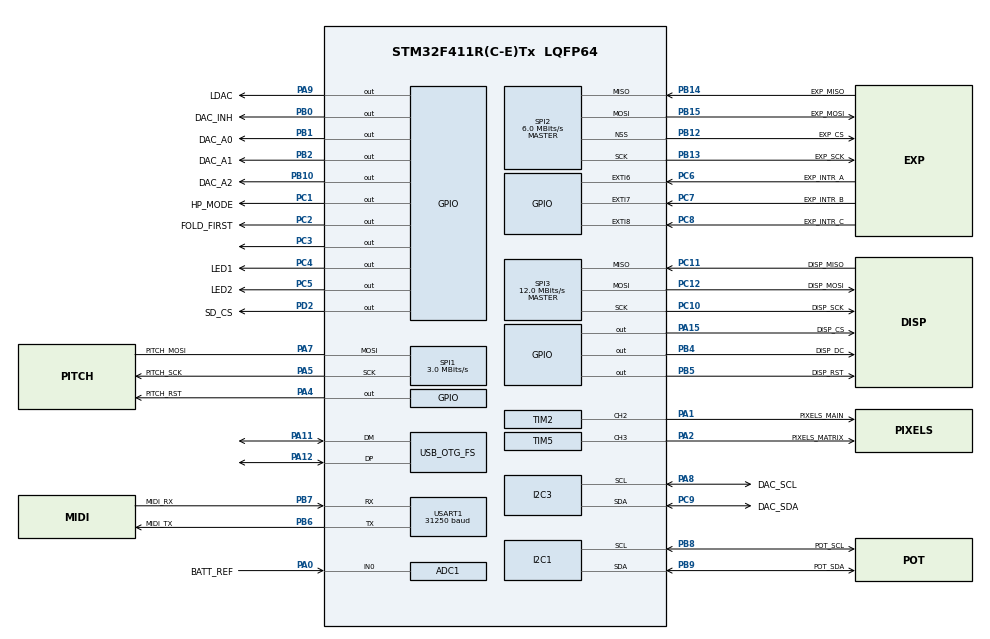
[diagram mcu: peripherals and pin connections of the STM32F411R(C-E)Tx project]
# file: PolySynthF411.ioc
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ADC1.Channel-2\#ChannelRegularConversion=ADC_CHANNEL_0
ADC1.NbrOfConversionFlag=1
ADC1.Rank-2\#ChannelRegularConversion=1
ADC1.SamplingTime-2\#ChannelRegularConversion=ADC_SAMPLETIME_3CYCLES
ADC1.master=1
Dma.I2C3_TX.2.Direction=DMA_MEMORY_TO_PERIPH
Dma.I2C3_TX.2.FIFOMode=DMA_FIFOMODE_DISABLE
Dma.I2C3_TX.2.Instance=DMA1_Stream4
Dma.I2C3_TX.2.MemDataAlignment=DMA_MDATAALIGN_BYTE
Dma.I2C3_TX.2.MemInc=DMA_MINC_ENABLE
Dma.I2C3_TX.2.Mode=DMA_NORMAL
Dma.I2C3_TX.2.PeriphDataAlignment=DMA_PDATAALIGN_BYTE
Dma.I2C3_TX.2.PeriphInc=DMA_PINC_DISABLE
Dma.I2C3_TX.2.Priority=DMA_PRIORITY_LOW
Dma.Request0=TIM5_CH3/UP
Dma.Request1=TIM2_CH2/CH4
Dma.Request2=I2C3_TX
Dma.Request3=SPI3_TX
Dma.Request4=SPI1_TX
Dma.SPI1_TX.4.Direction=DMA_MEMORY_TO_PERIPH
Dma.SPI1_TX.4.FIFOMode=DMA_FIFOMODE_DISABLE
Dma.SPI1_TX.4.Instance=DMA2_Stream2
Dma.SPI1_TX.4.MemDataAlignment=DMA_MDATAALIGN_HALFWORD
Dma.SPI1_TX.4.MemInc=DMA_MINC_ENABLE
Dma.SPI1_TX.4.Mode=DMA_CIRCULAR
Dma.SPI1_TX.4.PeriphDataAlignment=DMA_PDATAALIGN_HALFWORD
Dma.SPI1_TX.4.PeriphInc=DMA_PINC_DISABLE
Dma.SPI1_TX.4.Priority=DMA_PRIORITY_LOW
Dma.SPI3_TX.3.Direction=DMA_MEMORY_TO_PERIPH
Dma.SPI3_TX.3.FIFOMode=DMA_FIFOMODE_DISABLE
Dma.SPI3_TX.3.Instance=DMA1_Stream5
Dma.SPI3_TX.3.MemDataAlignment=DMA_MDATAALIGN_BYTE
Dma.SPI3_TX.3.MemInc=DMA_MINC_ENABLE
Dma.SPI3_TX.3.Mode=DMA_NORMAL
Dma.SPI3_TX.3.PeriphDataAlignment=DMA_PDATAALIGN_BYTE
Dma.SPI3_TX.3.PeriphInc=DMA_PINC_DISABLE
Dma.SPI3_TX.3.Priority=DMA_PRIORITY_LOW
Dma.TIM2_CH2/CH4.1.Direction=DMA_MEMORY_TO_PERIPH
Dma.TIM2_CH2/CH4.1.FIFOMode=DMA_FIFOMODE_DISABLE
Dma.TIM2_CH2/CH4.1.Instance=DMA1_Stream6
Dma.TIM2_CH2/CH4.1.MemDataAlignment=DMA_MDATAALIGN_HALFWORD
Dma.TIM2_CH2/CH4.1.MemInc=DMA_MINC_ENABLE
Dma.TIM2_CH2/CH4.1.Mode=DMA_CIRCULAR
Dma.TIM2_CH2/CH4.1.PeriphDataAlignment=DMA_PDATAALIGN_HALFWORD
Dma.TIM2_CH2/CH4.1.PeriphInc=DMA_PINC_DISABLE
Dma.TIM2_CH2/CH4.1.Priority=DMA_PRIORITY_LOW
Dma.TIM5_CH3/UP.0.Direction=DMA_MEMORY_TO_PERIPH
Dma.TIM5_CH3/UP.0.FIFOMode=DMA_FIFOMODE_DISABLE
Dma.TIM5_CH3/UP.0.Instance=DMA1_Stream0
Dma.TIM5_CH3/UP.0.MemDataAlignment=DMA_MDATAALIGN_HALFWORD
Dma.TIM5_CH3/UP.0.MemInc=DMA_MINC_ENABLE
Dma.TIM5_CH3/UP.0.Mode=DMA_CIRCULAR
Dma.TIM5_CH3/UP.0.PeriphDataAlignment=DMA_PDATAALIGN_HALFWORD
Dma.TIM5_CH3/UP.0.PeriphInc=DMA_PINC_DISABLE
Dma.TIM5_CH3/UP.0.Priority=DMA_PRIORITY_LOW
FATFS._MAX_SS=4096
FATFS._USE_LFN=1
I2C3.I2C_Mode=I2C_Fast
Mcu.Family=STM32F4
Mcu.Name=STM32F411R(C-E)Tx
Mcu.Package=LQFP64
NVIC.DMA1_Stream0_IRQn=true\:0\:0\:false\:false\:true\:false\:true\:true
NVIC.DMA1_Stream4_IRQn=true\:0\:0\:false\:false\:true\:false\:true\:true
NVIC.DMA1_Stream5_IRQn=true\:0\:0\:false\:false\:true\:false\:true\:true
NVIC.DMA1_Stream6_IRQn=true\:0\:0\:false\:false\:true\:false\:true\:true
NVIC.DMA2_Stream2_IRQn=true\:0\:0\:false\:false\:true\:false\:true\:true
NVIC.EXTI9_5_IRQn=true\:0\:0\:false\:false\:true\:true\:true\:true
NVIC.PriorityGroup=NVIC_PRIORITYGROUP_4
NVIC.TIM1_BRK_TIM9_IRQn=true\:0\:0\:false\:false\:true\:true\:true\:true
NVIC.TIM4_IRQn=true\:0\:0\:false\:false\:true\:true\:true\:true
NVIC.USART1_IRQn=true\:0\:0\:false\:false\:true\:true\:true\:true
PA0-WKUP.GPIO_Label=BATT_REF
PA0-WKUP.Signal=ADCx_IN0
PA1.GPIO_Label=PIXELS_MAIN
PA1.Signal=S_TIM2_CH2
PA11.Mode=Device_Only
PA11.Signal=USB_OTG_FS_DM
PA12.Mode=Device_Only
PA12.Signal=USB_OTG_FS_DP
PA13.Mode=Trace_Asynchronous_SW
PA13.Signal=SYS_JTMS-SWDIO
PA14.Mode=Trace_Asynchronous_SW
PA14.Signal=SYS_JTCK-SWCLK
PA15.GPIO_Label=DISP_CS
PA15.Signal=GPIO_Output
PA2.GPIO_Label=PIXELS_MATRIX
PA2.Signal=S_TIM5_CH3
PA4.GPIO_Label=PITCH_RST
PA4.Signal=GPIO_Output
PA5.GPIO_Label=PITCH_SCK
PA5.Mode=Simplex_Bidirectional_Master
PA5.Signal=SPI1_SCK
PA7.GPIO_Label=PITCH_MOSI
PA7.Mode=Simplex_Bidirectional_Master
PA7.Signal=SPI1_MOSI
PA8.GPIO_Label=DAC_SCL
PA8.Mode=I2C
PA8.Signal=I2C3_SCL
PA9.GPIO_Label=LDAC
PA9.Signal=GPIO_Output
PB0.GPIO_Label=DAC_INH
PB0.Signal=GPIO_Output
PB1.GPIO_Label=DAC_A0
PB1.Signal=GPIO_Output
PB10.GPIO_Label=DAC_A2
PB10.Signal=GPIO_Output
PB12.GPIO_Label=EXP_CS
PB12.Mode=NSS_Signal_Hard_Output
PB12.Signal=SPI2_NSS
PB13.GPIO_Label=EXP_SCK
PB13.Mode=Full_Duplex_Master
PB13.Signal=SPI2_SCK
PB14.GPIO_Label=EXP_MISO
PB14.Mode=Full_Duplex_Master
PB14.Signal=SPI2_MISO
PB15.GPIO_Label=EXP_MOSI
PB15.Mode=Full_Duplex_Master
PB15.Signal=SPI2_MOSI
PB2.GPIO_Label=DAC_A1
PB2.Signal=GPIO_Output
PB3.Mode=Trace_Asynchronous_SW
PB3.Signal=SYS_JTDO-SWO
PB4.GPIO_Label=DISP_DC
PB4.Signal=GPIO_Output
PB5.GPIO_Label=DISP_RST
PB5.Signal=GPIO_Output
PB6.GPIO_Label=MIDI_TX
PB6.Mode=Asynchronous
PB6.Signal=USART1_TX
PB7.GPIO_Label=MIDI_RX
PB7.Mode=Asynchronous
PB7.Signal=USART1_RX
PB8.GPIO_Label=POT_SCL
PB8.Mode=I2C
PB8.Signal=I2C1_SCL
PB9.GPIO_Label=POT_SDA
PB9.Mode=I2C
PB9.Signal=I2C1_SDA
PC1.GPIO_Label=HP_MODE
PC1.Signal=GPIO_Output
PC10.GPIO_Label=DISP_SCK
PC10.Mode=Full_Duplex_Master
PC10.Signal=SPI3_SCK
PC11.GPIO_Label=DISP_MISO
PC11.Mode=Full_Duplex_Master
PC11.Signal=SPI3_MISO
PC12.GPIO_Label=DISP_MOSI
PC12.Mode=Full_Duplex_Master
PC12.Signal=SPI3_MOSI
PC14-OSC32_IN.Mode=LSE-External-Oscillator
PC14-OSC32_IN.Signal=RCC_OSC32_IN
PC15-OSC32_OUT.Mode=LSE-External-Oscillator
PC15-OSC32_OUT.Signal=RCC_OSC32_OUT
PC2.GPIO_Label=FOLD_FIRST
PC2.Signal=GPIO_Output
PC3.Signal=GPIO_Output
PC4.GPIO_Label=LED1
PC4.Signal=GPIO_Output
PC5.GPIO_Label=LED2
PC5.Signal=GPIO_Output
PC6.GPIO_Label=EXP_INTR_A
PC6.Signal=GPXTI6
PC7.GPIO_Label=EXP_INTR_B
PC7.Signal=GPXTI7
PC8.GPIO_Label=EXP_INTR_C
PC8.Signal=GPXTI8
PC9.GPIO_Label=DAC_SDA
PC9.Mode=I2C
PC9.Signal=I2C3_SDA
PD2.GPIO_Label=SD_CS
PD2.Signal=GPIO_Output
PH0\ -\ OSC_IN.Mode=HSE-External-Oscillator
PH0\ -\ OSC_IN.Signal=RCC_OSC_IN
PH1\ -\ OSC_OUT.Mode=HSE-External-Oscillator
PH1\ -\ OSC_OUT.Signal=RCC_OSC_OUT
ProjectManager.HeapSize=0x200
ProjectManager.StackSize=0x400
ProjectManager.TargetToolchain=STM32CubeIDE
RCC.48MHZClocksFreq_Value=48000000
RCC.AHBCLKDivider=RCC_SYSCLK_DIV2
RCC.AHBFreq_Value=48000000
RCC.APB1Freq_Value=48000000
RCC.APB1TimFreq_Value=48000000
RCC.APB2Freq_Value=48000000
RCC.APB2TimFreq_Value=48000000
RCC.CortexFreq_Value=48000000
RCC.HCLKFreq_Value=48000000
RCC.HSE_VALUE=16000000
RCC.HSI_VALUE=16000000
RCC.PLLM=8
RCC.PLLN=96
RCC.SYSCLKFreq_VALUE=96000000
RCC.SYSCLKSource=RCC_SYSCLKSOURCE_PLLCLK
RCC.VCOOutputFreq_Value=192000000
SH.ADCx_IN0.0=ADC1_IN0,IN0
SH.S_TIM2_CH2.0=TIM2_CH2,PWM Generation2 CH2
SH.S_TIM5_CH3.0=TIM5_CH3,PWM Generation3 CH3
SPI1.BaudRatePrescaler=SPI_BAUDRATEPRESCALER_16
SPI1.CalculateBaudRate=3.0 MBits/s
SPI1.Direction=SPI_DIRECTION_1LINE
SPI1.Mode=SPI_MODE_MASTER
SPI1.VirtualType=VM_MASTER
SPI2.BaudRatePrescaler=SPI_BAUDRATEPRESCALER_8
SPI2.CalculateBaudRate=6.0 MBits/s
SPI2.Direction=SPI_DIRECTION_2LINES
SPI2.Mode=SPI_MODE_MASTER
SPI2.VirtualNSS=VM_NSSHARD
SPI2.VirtualType=VM_MASTER
SPI3.BaudRatePrescaler=SPI_BAUDRATEPRESCALER_4
SPI3.CalculateBaudRate=12.0 MBits/s
SPI3.Direction=SPI_DIRECTION_2LINES
SPI3.Mode=SPI_MODE_MASTER
SPI3.VirtualType=VM_MASTER
TIM2.Channel-PWM\ Generation2\ CH2=TIM_CHANNEL_2
TIM2.Period=60 - 1
TIM4.Period=40000
TIM4.Prescaler=8
TIM5.Channel-PWM\ Generation3\ CH3=TIM_CHANNEL_3
TIM5.Period=60 - 1
TIM9.Period=4799
TIM9.Prescaler=1
USART1.BaudRate=31250
USART1.VirtualMode=VM_ASYNC
USB_OTG_FS.VirtualMode=Device_Only
VP_FATFS_VS_Generic.Mode=User_defined
VP_TIM4_VS_ClockSourceINT.Mode=Internal
VP_TIM9_VS_ClockSourceINT.Mode=Internal
board=custom

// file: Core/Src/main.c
/* USER CODE BEGIN Header */
/**
 ******************************************************************************
 * @file           : main.c
 * @brief          : Main program body
 ******************************************************************************
 * @attention
 *
 * Copyright (c) 2024 STMicroelectronics.
 * All rights reserved.
 *
 * This software is licensed under terms that can be found in the LICENSE file
 * in the root directory of this software component.
 * If no LICENSE file comes with this software, it is provided AS-IS.
 *
 ******************************************************************************
 */
/* USER CODE END Header */
#include "main.h"
#include "fatfs.h"

/* USER CODE BEGIN Includes */
#include <stdio.h>
#include <string.h>
#include <stdarg.h>
#include "VoiceClock.h"
#include "ControlVoltage.h"
#include "SynthProcessor.h"

/* USER CODE END Includes */

ADC_HandleTypeDef hadc1;

I2C_HandleTypeDef hi2c1;
I2C_HandleTypeDef hi2c3;
DMA_HandleTypeDef hdma_i2c3_tx;

SPI_HandleTypeDef hspi1;
SPI_HandleTypeDef hspi2;
SPI_HandleTypeDef hspi3;
DMA_HandleTypeDef hdma_spi1_tx;
DMA_HandleTypeDef hdma_spi3_tx;

TIM_HandleTypeDef htim2;
TIM_HandleTypeDef htim4;
TIM_HandleTypeDef htim5;
TIM_HandleTypeDef htim9;
DMA_HandleTypeDef hdma_tim2_ch2_ch4;
DMA_HandleTypeDef hdma_tim5_ch3_up;

UART_HandleTypeDef huart1;

/* USER CODE BEGIN PV */

//Voice Clock Stuff------------------
voice_clock_t vClk;
volatile uint8_t vclkHalfNeeded = 0;
volatile uint8_t vclkFullNeeded = 0;
// DAC Stuff----------------------------------
dacLevels_t voiceLevels[6];
volatile uint8_t dacLevelsNeeded = 0;

volatile uint8_t dacTransmissionFinished = 0;
volatile uint8_t currentDacVoice = 0;

//MIDI stuff-------------------------
uint8_t currentMidiByte = 0;
volatile uint8_t midiMsgReady = 0;

// Display stuff-------------
display_queue_t mainDispQueue;

// Processor stuff-----------
button_processor_t buttonProc;
enc_processor_t encoderProc;
graphics_processor_t graphicsProc;
pixel_processor_t pixelProc;
synth_processor_t synthProc;

//Filesystem stuff-----------
//FATFS fatFS;
uint8_t SD_INITIALIZED = 0;

//------------------------------------
/* USER CODE END PV */

void SystemClock_Config(void);
static void MX_GPIO_Init(void);
static void MX_DMA_Init(void);
static void MX_I2C1_Init(void);
static void MX_I2C3_Init(void);
static void MX_SPI1_Init(void);
static void MX_SPI2_Init(void);
static void MX_SPI3_Init(void);
static void MX_USART1_UART_Init(void);
static void MX_TIM2_Init(void);
static void MX_TIM5_Init(void);
static void MX_ADC1_Init(void);
static void MX_TIM4_Init(void);
static void MX_TIM9_Init(void);
/* USER CODE BEGIN PFP */

void encoderTurn(uint8_t enc, uint8_t clockwise);
void onClick(uint8_t btn);
void onPressStart(uint8_t btn);
void onPressEnd(uint8_t btn);
void duringPress(uint8_t btn);
/* USER CODE END PFP */

/* USER CODE BEGIN 0 */

uint8_t nextVoiceToUpdate() {
	uint8_t voice = currentDacVoice;
	for (uint8_t i = 0; i < 6; i++) {
		voice = (voice + 1) % 6;
		for (uint8_t cv = 0; cv < 7; cv++) {
			if (voiceLevels[voice].currentData[cv]
					!= voiceLevels[voice].prevData[cv])
				return voice;
		}
	}
	return 6;
}

//===================================================================================
//SPI DMA Callbacks and helpers ------------------

void HAL_SPI_TxHalfCpltCallback(SPI_HandleTypeDef *hspi) {
	if (hspi == &hspi1) {
		vclkHalfNeeded = 1;
		//tx_half_complete(vClk);
	}

}

void HAL_SPI_TxCpltCallback(SPI_HandleTypeDef *hspi) {
	if (hspi == &hspi1) { // voices are done
		//TODO: this should render the first half of the buffer
		vclkFullNeeded = 1;
		//tx_complete(vClk);
	} else if (hspi == &hspi3) {
		// pull CS high again
		ILI9341_Unselect();
		// alert the processor
		disp_dma_finished(graphicsProc);

	}
}

void HAL_I2C_TxCpltCallback(I2C_HandleTypeDef *i2c) {

	if (i2c == &hi2c3) { // our DAC is done updating to the current channel
		//1. set the mux to charge the capacitors appropriately
		finishVoiceUpdate_DMA(currentDacVoice);
		// 2. check if we have another voice to update
		uint8_t v = nextVoiceToUpdate();
		// 3. Update the voice if needed, set the flag to indicate we're finished otherwise
		if (v < 6) { // we have another update to do
			currentDacVoice = v;
			startVoiceUpdate_DMA(i2c, &voiceLevels[v].currentData[0],
					&voiceLevels[v].prevData[0]);

		} else { // we're finished
			currentDacVoice = 0;
			dacTransmissionFinished = 1;

		}
	}
}

// Timer Callbacks--------------------------------------------------

void HAL_TIM_PeriodElapsedCallback(TIM_HandleTypeDef *timer) {

	if (timer == &htim9) {
		TickTimer_tick();
	} else if (timer == &htim4) {
		// ask the main process for new CV data
		dacLevelsNeeded = 1;
		// if we aren't already mid-transmission, check if we need to transmit anything
		if (dacTransmissionFinished) {
			uint8_t v = nextVoiceToUpdate();
			if (v < 6) {
				dacTransmissionFinished = 0;
				currentDacVoice = v;
				startVoiceUpdate_DMA(&hi2c3, &voiceLevels[v].currentData[0],
						&voiceLevels[v].prevData[0]);
			}
		}
	}
}

void HAL_TIM_PWM_PulseFinishedHalfCpltCallback(TIM_HandleTypeDef *htim) {
	pixel_tx_half_complete(pixelProc, htim);
}

void HAL_TIM_PWM_PulseFinishedCallback(TIM_HandleTypeDef *htim) {
	pixel_tx_complete(pixelProc, htim);
}

// UART callbacks for MIDI stuff ---------
void HAL_UART_RxCpltCallback(UART_HandleTypeDef *huart) {

	// we receive MIDI messages one byte at a time
	midiMsgReady = MIDI_receiveByte(currentMidiByte);
	HAL_UART_Receive_IT(huart, &currentMidiByte, 1);
}
//-----------------------------------------------------------------

int __io_putchar(int ch) {
	// Write character to ITM ch.0
	ITM_SendChar(ch);
	return (ch);
}

//------------------------------------

/* USER CODE END 0 */

int main(void)
{

  /* MCU Configuration--------------------------------------------------------*/

  /* Reset of all peripherals, Initializes the Flash interface and the Systick. */
  HAL_Init();

  /* Configure the system clock */
  SystemClock_Config();

  /* USER CODE BEGIN SysInit */
	// init the RNG
  /* USER CODE END SysInit */

  /* Initialize all configured peripherals */
  MX_GPIO_Init();
  MX_DMA_Init();
  MX_I2C1_Init();
  MX_I2C3_Init();
  MX_SPI1_Init();
  MX_SPI2_Init();
  MX_SPI3_Init();
  MX_USART1_UART_Init();
  MX_TIM2_Init();
  MX_TIM5_Init();
  MX_ADC1_Init();
  MX_TIM4_Init();
  MX_TIM9_Init();
  MX_FATFS_Init();
  /* USER CODE BEGIN 2 */
	//allocate the display queue
	mainDispQueue = create_display_queue();
	// allocate the processors
	buttonProc = create_button_processor();
	encoderProc = create_enc_processor();
	graphicsProc = create_graphics_processor();
	pixelProc = create_pixel_processor();
	synthProc = create_synth_processor(vClk, encoderProc, buttonProc,
			graphicsProc, pixelProc);
	init_pixels(pixelProc);
	// init the file system
	init_file_system(synthProc);

	// initialize the MCP23S17 interrupts for the encoders
	enc_init_interrupts(encoderProc);

	// attach the callbacks
	enc_register_callback(encoderProc, &encoderTurn);
	set_on_click(buttonProc, &onClick);
	set_on_press_start(buttonProc, &onPressStart);
	set_on_press_end(buttonProc, &onPressEnd);
	set_during_press(buttonProc, &duringPress);

//	// initialize the SD card
//	if(f_mount(&fatFS, "", 1) != FR_OK){
//		Error_Handler();
//	} else {
//		SD_INITIALIZED = 1;
//	}

	// reset the counter ICs before we start the first transmission
	HAL_GPIO_WritePin(PITCH_RST_GPIO_Port, PITCH_RST_Pin, GPIO_PIN_SET);
	HAL_GPIO_WritePin(PITCH_RST_GPIO_Port, PITCH_RST_Pin, GPIO_PIN_RESET);
	// do the first DMA transmission outside the while loop to start
	begin(vClk, &hspi1);

	// start the timer to update the CVs
	if (HAL_TIM_Base_Start_IT(&htim4) != HAL_OK) {
		Error_Handler();
	}

	// start the first interrupt receive for MIDI
	HAL_UART_Receive_IT(&huart1, &currentMidiByte, 1);

	// seed our RNG

  /* USER CODE END 2 */

  /* Infinite loop */
  /* USER CODE BEGIN WHILE */
	tick_t lastButtonCheck = 0;
	tick_t now = 0;
#ifdef DAC_UPDATE_OPTIMIZE
	tick_t lastDacUpdate = 0;
	float deltaMs = 0.0f;
#endif

	while (1) {

		//process any MIDI messages here
		if (midiMsgReady) {
			midi_t msg = MIDI_getLatestMessage();
			process_midi_msg(synthProc, msg);
			midiMsgReady = 0;
		}

		// calculate next pitch buffer if needed
		if(vclkHalfNeeded){
			tx_half_complete(vClk);
			vclkHalfNeeded = 0;
			// we can do else if bc only one of these flags
			// will be true at any given time
		} else if (vclkFullNeeded){
			tx_complete(vClk);
			vclkFullNeeded = 0;
		}
		//=====================================

		now = TickTimer_get();

		if (dacLevelsNeeded) {
#ifndef DAC_UPDATE_OPTIMIZE
			update_dac_levels(synthProc, voiceLevels);
#else
			deltaMs = TickTimer_tickDistanceMs(lastDacUpdate, now);
			lastDacUpdate = now;
			update_dac_levels(synthProc, voiceLevels, deltaMs);
#endif
			dacLevelsNeeded = 0;
		}
		// send the next DMA chunk to the display if needed
		check_gui_updates(synthProc);
		// see if we need pixel updates
		tick_pixel_processor(pixelProc);
		// see if it's time to check the buttons
		if (TickTimer_tickDistanceMs(lastButtonCheck,
				now) > BUTTON_CHECK_INTERVAL) {
			check_buttons(buttonProc);
			lastButtonCheck = now;
		}
    /* USER CODE END WHILE */

	}
}

void SystemClock_Config(void)
{
  RCC_OscInitTypeDef RCC_OscInitStruct = {0};
  RCC_ClkInitTypeDef RCC_ClkInitStruct = {0};

  /** Configure the main internal regulator output voltage
  */
  __HAL_RCC_PWR_CLK_ENABLE();
  __HAL_PWR_VOLTAGESCALING_CONFIG(PWR_REGULATOR_VOLTAGE_SCALE1);

  /** Initializes the RCC Oscillators according to the specified parameters
  * in the RCC_OscInitTypeDef structure.
  */
  RCC_OscInitStruct.OscillatorType = RCC_OSCILLATORTYPE_HSI;
  RCC_OscInitStruct.HSIState = RCC_HSI_ON;
  RCC_OscInitStruct.HSICalibrationValue = RCC_HSICALIBRATION_DEFAULT;
  RCC_OscInitStruct.PLL.PLLState = RCC_PLL_ON;
  RCC_OscInitStruct.PLL.PLLSource = RCC_PLLSOURCE_HSI;
  RCC_OscInitStruct.PLL.PLLM = 8;
  RCC_OscInitStruct.PLL.PLLN = 64;
  RCC_OscInitStruct.PLL.PLLP = RCC_PLLP_DIV2;
  RCC_OscInitStruct.PLL.PLLQ = 4;
  if (HAL_RCC_OscConfig(&RCC_OscInitStruct) != HAL_OK)
  {
    Error_Handler();
  }

  /** Initializes the CPU, AHB and APB buses clocks
  */
  RCC_ClkInitStruct.ClockType = RCC_CLOCKTYPE_HCLK|RCC_CLOCKTYPE_SYSCLK
                              |RCC_CLOCKTYPE_PCLK1|RCC_CLOCKTYPE_PCLK2;
  RCC_ClkInitStruct.SYSCLKSource = RCC_SYSCLKSOURCE_PLLCLK;
  RCC_ClkInitStruct.AHBCLKDivider = RCC_SYSCLK_DIV1;
  RCC_ClkInitStruct.APB1CLKDivider = RCC_HCLK_DIV2;
  RCC_ClkInitStruct.APB2CLKDivider = RCC_HCLK_DIV1;

  if (HAL_RCC_ClockConfig(&RCC_ClkInitStruct, FLASH_LATENCY_0) != HAL_OK)
  {
    Error_Handler();
  }
}

static void MX_ADC1_Init(void)
{

  ADC_ChannelConfTypeDef sConfig = {0};

  /** Configure the global features of the ADC (Clock, Resolution, Data Alignment and number of conversion)
  */
  hadc1.Instance = ADC1;
  hadc1.Init.ClockPrescaler = ADC_CLOCK_SYNC_PCLK_DIV2;
  hadc1.Init.Resolution = ADC_RESOLUTION_12B;
  hadc1.Init.ScanConvMode = DISABLE;
  hadc1.Init.ContinuousConvMode = DISABLE;
  hadc1.Init.DiscontinuousConvMode = DISABLE;
  hadc1.Init.ExternalTrigConvEdge = ADC_EXTERNALTRIGCONVEDGE_NONE;
  hadc1.Init.ExternalTrigConv = ADC_SOFTWARE_START;
  hadc1.Init.DataAlign = ADC_DATAALIGN_RIGHT;
  hadc1.Init.NbrOfConversion = 1;
  hadc1.Init.DMAContinuousRequests = DISABLE;
  hadc1.Init.EOCSelection = ADC_EOC_SINGLE_CONV;
  if (HAL_ADC_Init(&hadc1) != HAL_OK)
  {
    Error_Handler();
  }

  /** Configure for the selected ADC regular channel its corresponding rank in the sequencer and its sample time.
  */
  sConfig.Channel = ADC_CHANNEL_0;
  sConfig.Rank = 1;
  sConfig.SamplingTime = ADC_SAMPLETIME_3CYCLES;
  if (HAL_ADC_ConfigChannel(&hadc1, &sConfig) != HAL_OK)
  {
    Error_Handler();
  }

}

static void MX_I2C1_Init(void)
{

  hi2c1.Instance = I2C1;
  hi2c1.Init.ClockSpeed = 100000;
  hi2c1.Init.DutyCycle = I2C_DUTYCYCLE_2;
  hi2c1.Init.OwnAddress1 = 0;
  hi2c1.Init.AddressingMode = I2C_ADDRESSINGMODE_7BIT;
  hi2c1.Init.DualAddressMode = I2C_DUALADDRESS_DISABLE;
  hi2c1.Init.OwnAddress2 = 0;
  hi2c1.Init.GeneralCallMode = I2C_GENERALCALL_DISABLE;
  hi2c1.Init.NoStretchMode = I2C_NOSTRETCH_DISABLE;
  if (HAL_I2C_Init(&hi2c1) != HAL_OK)
  {
    Error_Handler();
  }

}

static void MX_I2C3_Init(void)
{

  hi2c3.Instance = I2C3;
  hi2c3.Init.ClockSpeed = 400000;
  hi2c3.Init.DutyCycle = I2C_DUTYCYCLE_2;
  hi2c3.Init.OwnAddress1 = 0;
  hi2c3.Init.AddressingMode = I2C_ADDRESSINGMODE_7BIT;
  hi2c3.Init.DualAddressMode = I2C_DUALADDRESS_DISABLE;
  hi2c3.Init.OwnAddress2 = 0;
  hi2c3.Init.GeneralCallMode = I2C_GENERALCALL_DISABLE;
  hi2c3.Init.NoStretchMode = I2C_NOSTRETCH_DISABLE;
  if (HAL_I2C_Init(&hi2c3) != HAL_OK)
  {
    Error_Handler();
  }

}

static void MX_SPI1_Init(void)
{

  /* SPI1 parameter configuration*/
  hspi1.Instance = SPI1;
  hspi1.Init.Mode = SPI_MODE_MASTER;
  hspi1.Init.Direction = SPI_DIRECTION_1LINE;
  hspi1.Init.DataSize = SPI_DATASIZE_8BIT;
  hspi1.Init.CLKPolarity = SPI_POLARITY_LOW;
  hspi1.Init.CLKPhase = SPI_PHASE_1EDGE;
  hspi1.Init.NSS = SPI_NSS_SOFT;
  hspi1.Init.BaudRatePrescaler = SPI_BAUDRATEPRESCALER_16;
  hspi1.Init.FirstBit = SPI_FIRSTBIT_MSB;
  hspi1.Init.TIMode = SPI_TIMODE_DISABLE;
  hspi1.Init.CRCCalculation = SPI_CRCCALCULATION_DISABLE;
  hspi1.Init.CRCPolynomial = 10;
  if (HAL_SPI_Init(&hspi1) != HAL_OK)
  {
    Error_Handler();
  }
  /* USER CODE BEGIN SPI1_Init 2 */
	//init our voice clock
	vClk = create_voice_clock();
  /* USER CODE END SPI1_Init 2 */

}

static void MX_SPI2_Init(void)
{

  /* SPI2 parameter configuration*/
  hspi2.Instance = SPI2;
  hspi2.Init.Mode = SPI_MODE_MASTER;
  hspi2.Init.Direction = SPI_DIRECTION_2LINES;
  hspi2.Init.DataSize = SPI_DATASIZE_8BIT;
  hspi2.Init.CLKPolarity = SPI_POLARITY_LOW;
  hspi2.Init.CLKPhase = SPI_PHASE_1EDGE;
  hspi2.Init.NSS = SPI_NSS_HARD_OUTPUT;
  hspi2.Init.BaudRatePrescaler = SPI_BAUDRATEPRESCALER_8;
  hspi2.Init.FirstBit = SPI_FIRSTBIT_MSB;
  hspi2.Init.TIMode = SPI_TIMODE_DISABLE;
  hspi2.Init.CRCCalculation = SPI_CRCCALCULATION_DISABLE;
  hspi2.Init.CRCPolynomial = 10;
  if (HAL_SPI_Init(&hspi2) != HAL_OK)
  {
    Error_Handler();
  }

}

static void MX_SPI3_Init(void)
{

  /* SPI3 parameter configuration*/
  hspi3.Instance = SPI3;
  hspi3.Init.Mode = SPI_MODE_MASTER;
  hspi3.Init.Direction = SPI_DIRECTION_2LINES;
  hspi3.Init.DataSize = SPI_DATASIZE_8BIT;
  hspi3.Init.CLKPolarity = SPI_POLARITY_LOW;
  hspi3.Init.CLKPhase = SPI_PHASE_1EDGE;
  hspi3.Init.NSS = SPI_NSS_SOFT;
  hspi3.Init.BaudRatePrescaler = SPI_BAUDRATEPRESCALER_4;
  hspi3.Init.FirstBit = SPI_FIRSTBIT_MSB;
  hspi3.Init.TIMode = SPI_TIMODE_DISABLE;
  hspi3.Init.CRCCalculation = SPI_CRCCALCULATION_DISABLE;
  hspi3.Init.CRCPolynomial = 10;
  if (HAL_SPI_Init(&hspi3) != HAL_OK)
  {
    Error_Handler();
  }

}

static void MX_TIM2_Init(void)
{

  TIM_MasterConfigTypeDef sMasterConfig = {0};
  TIM_OC_InitTypeDef sConfigOC = {0};

  htim2.Instance = TIM2;
  htim2.Init.Prescaler = 0;
  htim2.Init.CounterMode = TIM_COUNTERMODE_UP;
  htim2.Init.Period = 60 - 1;
  htim2.Init.ClockDivision = TIM_CLOCKDIVISION_DIV1;
  htim2.Init.AutoReloadPreload = TIM_AUTORELOAD_PRELOAD_DISABLE;
  if (HAL_TIM_PWM_Init(&htim2) != HAL_OK)
  {
    Error_Handler();
  }
  sMasterConfig.MasterOutputTrigger = TIM_TRGO_RESET;
  sMasterConfig.MasterSlaveMode = TIM_MASTERSLAVEMODE_DISABLE;
  if (HAL_TIMEx_MasterConfigSynchronization(&htim2, &sMasterConfig) != HAL_OK)
  {
    Error_Handler();
  }
  sConfigOC.OCMode = TIM_OCMODE_PWM1;
  sConfigOC.Pulse = 0;
  sConfigOC.OCPolarity = TIM_OCPOLARITY_HIGH;
  sConfigOC.OCFastMode = TIM_OCFAST_DISABLE;
  if (HAL_TIM_PWM_ConfigChannel(&htim2, &sConfigOC, TIM_CHANNEL_2) != HAL_OK)
  {
    Error_Handler();
  }
  HAL_TIM_MspPostInit(&htim2);

}

static void MX_TIM4_Init(void)
{

  TIM_ClockConfigTypeDef sClockSourceConfig = {0};
  TIM_MasterConfigTypeDef sMasterConfig = {0};

  htim4.Instance = TIM4;
  htim4.Init.Prescaler = 8;
  htim4.Init.CounterMode = TIM_COUNTERMODE_UP;
  htim4.Init.Period = 40000;
  htim4.Init.ClockDivision = TIM_CLOCKDIVISION_DIV1;
  htim4.Init.AutoReloadPreload = TIM_AUTORELOAD_PRELOAD_DISABLE;
  if (HAL_TIM_Base_Init(&htim4) != HAL_OK)
  {
    Error_Handler();
  }
  sClockSourceConfig.ClockSource = TIM_CLOCKSOURCE_INTERNAL;
  if (HAL_TIM_ConfigClockSource(&htim4, &sClockSourceConfig) != HAL_OK)
  {
    Error_Handler();
  }
  sMasterConfig.MasterOutputTrigger = TIM_TRGO_RESET;
  sMasterConfig.MasterSlaveMode = TIM_MASTERSLAVEMODE_DISABLE;
  if (HAL_TIMEx_MasterConfigSynchronization(&htim4, &sMasterConfig) != HAL_OK)
  {
    Error_Handler();
  }

}

static void MX_TIM5_Init(void)
{

  TIM_MasterConfigTypeDef sMasterConfig = {0};
  TIM_OC_InitTypeDef sConfigOC = {0};

  htim5.Instance = TIM5;
  htim5.Init.Prescaler = 0;
  htim5.Init.CounterMode = TIM_COUNTERMODE_UP;
  htim5.Init.Period = 60 - 1;
  htim5.Init.ClockDivision = TIM_CLOCKDIVISION_DIV1;
  htim5.Init.AutoReloadPreload = TIM_AUTORELOAD_PRELOAD_DISABLE;
  if (HAL_TIM_PWM_Init(&htim5) != HAL_OK)
  {
    Error_Handler();
  }
  sMasterConfig.MasterOutputTrigger = TIM_TRGO_RESET;
  sMasterConfig.MasterSlaveMode = TIM_MASTERSLAVEMODE_DISABLE;
  if (HAL_TIMEx_MasterConfigSynchronization(&htim5, &sMasterConfig) != HAL_OK)
  {
    Error_Handler();
  }
  sConfigOC.OCMode = TIM_OCMODE_PWM1;
  sConfigOC.Pulse = 0;
  sConfigOC.OCPolarity = TIM_OCPOLARITY_HIGH;
  sConfigOC.OCFastMode = TIM_OCFAST_DISABLE;
  if (HAL_TIM_PWM_ConfigChannel(&htim5, &sConfigOC, TIM_CHANNEL_3) != HAL_OK)
  {
    Error_Handler();
  }
  HAL_TIM_MspPostInit(&htim5);

}

static void MX_TIM9_Init(void)
{

  TIM_ClockConfigTypeDef sClockSourceConfig = {0};

  htim9.Instance = TIM9;
  htim9.Init.Prescaler = 1;
  htim9.Init.CounterMode = TIM_COUNTERMODE_UP;
  htim9.Init.Period = 4799;
  htim9.Init.ClockDivision = TIM_CLOCKDIVISION_DIV1;
  htim9.Init.AutoReloadPreload = TIM_AUTORELOAD_PRELOAD_DISABLE;
  if (HAL_TIM_Base_Init(&htim9) != HAL_OK)
  {
    Error_Handler();
  }
  sClockSourceConfig.ClockSource = TIM_CLOCKSOURCE_INTERNAL;
  if (HAL_TIM_ConfigClockSource(&htim9, &sClockSourceConfig) != HAL_OK)
  {
    Error_Handler();
  }
  /* USER CODE BEGIN TIM9_Init 2 */
	// set up our TickTimer
	TickTimer_setTickTime(&htim9.Init);
	if(HAL_TIM_Base_Start_IT(&htim9) != HAL_OK){
		Error_Handler();
	}

  /* USER CODE END TIM9_Init 2 */

}

static void MX_USART1_UART_Init(void)
{

  huart1.Instance = USART1;
  huart1.Init.BaudRate = 31250;
  huart1.Init.WordLength = UART_WORDLENGTH_8B;
  huart1.Init.StopBits = UART_STOPBITS_1;
  huart1.Init.Parity = UART_PARITY_NONE;
  huart1.Init.Mode = UART_MODE_TX_RX;
  huart1.Init.HwFlowCtl = UART_HWCONTROL_NONE;
  huart1.Init.OverSampling = UART_OVERSAMPLING_16;
  if (HAL_UART_Init(&huart1) != HAL_OK)
  {
    Error_Handler();
  }

}

static void MX_DMA_Init(void)
{

  /* DMA controller clock enable */
  __HAL_RCC_DMA1_CLK_ENABLE();
  __HAL_RCC_DMA2_CLK_ENABLE();

  /* DMA interrupt init */
  /* DMA1_Stream0_IRQn interrupt configuration */
  HAL_NVIC_SetPriority(DMA1_Stream0_IRQn, 0, 0);
  HAL_NVIC_EnableIRQ(DMA1_Stream0_IRQn);
  /* DMA1_Stream4_IRQn interrupt configuration */
  HAL_NVIC_SetPriority(DMA1_Stream4_IRQn, 0, 0);
  HAL_NVIC_EnableIRQ(DMA1_Stream4_IRQn);
  /* DMA1_Stream5_IRQn interrupt configuration */
  HAL_NVIC_SetPriority(DMA1_Stream5_IRQn, 0, 0);
  HAL_NVIC_EnableIRQ(DMA1_Stream5_IRQn);
  /* DMA1_Stream6_IRQn interrupt configuration */
  HAL_NVIC_SetPriority(DMA1_Stream6_IRQn, 0, 0);
  HAL_NVIC_EnableIRQ(DMA1_Stream6_IRQn);
  /* DMA2_Stream2_IRQn interrupt configuration */
  HAL_NVIC_SetPriority(DMA2_Stream2_IRQn, 0, 0);
  HAL_NVIC_EnableIRQ(DMA2_Stream2_IRQn);

}

static void MX_GPIO_Init(void)
{
  GPIO_InitTypeDef GPIO_InitStruct = {0};

  /* GPIO Ports Clock Enable */
  __HAL_RCC_GPIOC_CLK_ENABLE();
  __HAL_RCC_GPIOH_CLK_ENABLE();
  __HAL_RCC_GPIOA_CLK_ENABLE();
  __HAL_RCC_GPIOB_CLK_ENABLE();
  __HAL_RCC_GPIOD_CLK_ENABLE();

  /*Configure GPIO pin Output Level */
  HAL_GPIO_WritePin(GPIOC, HP_MODE_Pin|FOLD_FIRST_Pin|GPIO_PIN_3|LED1_Pin
                          |LED2_Pin, GPIO_PIN_RESET);

  /*Configure GPIO pin Output Level */
  HAL_GPIO_WritePin(GPIOA, PITCH_RST_Pin|LDAC_Pin|DISP_CS_Pin, GPIO_PIN_RESET);

  /*Configure GPIO pin Output Level */
  HAL_GPIO_WritePin(GPIOB, DAC_INH_Pin|DAC_A0_Pin|DAC_A1_Pin|DAC_A2_Pin
                          |DISP_DC_Pin|DISP_RST_Pin, GPIO_PIN_RESET);

  /*Configure GPIO pin Output Level */
  HAL_GPIO_WritePin(SD_CS_GPIO_Port, SD_CS_Pin, GPIO_PIN_RESET);

  /*Configure GPIO pins : HP_MODE_Pin FOLD_FIRST_Pin PC3 LED1_Pin
                           LED2_Pin */
  GPIO_InitStruct.Pin = HP_MODE_Pin|FOLD_FIRST_Pin|GPIO_PIN_3|LED1_Pin
                          |LED2_Pin;
  GPIO_InitStruct.Mode = GPIO_MODE_OUTPUT_PP;
  GPIO_InitStruct.Pull = GPIO_NOPULL;
  GPIO_InitStruct.Speed = GPIO_SPEED_FREQ_LOW;
  HAL_GPIO_Init(GPIOC, &GPIO_InitStruct);

  /*Configure GPIO pins : PITCH_RST_Pin LDAC_Pin DISP_CS_Pin */
  GPIO_InitStruct.Pin = PITCH_RST_Pin|LDAC_Pin|DISP_CS_Pin;
  GPIO_InitStruct.Mode = GPIO_MODE_OUTPUT_PP;
  GPIO_InitStruct.Pull = GPIO_NOPULL;
  GPIO_InitStruct.Speed = GPIO_SPEED_FREQ_LOW;
  HAL_GPIO_Init(GPIOA, &GPIO_InitStruct);

  /*Configure GPIO pins : DAC_INH_Pin DAC_A0_Pin DAC_A1_Pin DAC_A2_Pin
                           DISP_DC_Pin DISP_RST_Pin */
  GPIO_InitStruct.Pin = DAC_INH_Pin|DAC_A0_Pin|DAC_A1_Pin|DAC_A2_Pin
                          |DISP_DC_Pin|DISP_RST_Pin;
  GPIO_InitStruct.Mode = GPIO_MODE_OUTPUT_PP;
  GPIO_InitStruct.Pull = GPIO_NOPULL;
  GPIO_InitStruct.Speed = GPIO_SPEED_FREQ_LOW;
  HAL_GPIO_Init(GPIOB, &GPIO_InitStruct);

  /*Configure GPIO pins : EXP_INTR_A_Pin EXP_INTR_B_Pin EXP_INTR_C_Pin */
  GPIO_InitStruct.Pin = EXP_INTR_A_Pin|EXP_INTR_B_Pin|EXP_INTR_C_Pin;
  GPIO_InitStruct.Mode = GPIO_MODE_IT_RISING;
  GPIO_InitStruct.Pull = GPIO_NOPULL;
  HAL_GPIO_Init(GPIOC, &GPIO_InitStruct);

  /*Configure GPIO pin : SD_CS_Pin */
  GPIO_InitStruct.Pin = SD_CS_Pin;
  GPIO_InitStruct.Mode = GPIO_MODE_OUTPUT_PP;
  GPIO_InitStruct.Pull = GPIO_NOPULL;
  GPIO_InitStruct.Speed = GPIO_SPEED_FREQ_LOW;
  HAL_GPIO_Init(SD_CS_GPIO_Port, &GPIO_InitStruct);

  /* EXTI interrupt init*/
  HAL_NVIC_SetPriority(EXTI9_5_IRQn, 0, 0);
  HAL_NVIC_EnableIRQ(EXTI9_5_IRQn);

/* USER CODE BEGIN MX_GPIO_Init_2 */

	// pull our pitch reset low
	HAL_GPIO_WritePin(PITCH_RST_GPIO_Port, PITCH_RST_Pin, GPIO_PIN_RESET);
	// we're not using hardware CS handling so we need to pull these high
	HAL_GPIO_WritePin(SD_CS_GPIO_Port, SD_CS_Pin, GPIO_PIN_SET);
	HAL_GPIO_WritePin(DISP_CS_GPIO_Port, DISP_CS_Pin, GPIO_PIN_SET);

/* USER CODE END MX_GPIO_Init_2 */
}

/* USER CODE BEGIN 4 */

// Hardware interrupt callback
void HAL_GPIO_EXTI_Callback(uint16_t pin) {
	switch (pin) {
	case EXP_INTR_A_Pin: // expander 2 port B
		enc_interrupt_sent(encoderProc, EXP_2_ADDR, 1);
		break;
	case EXP_INTR_B_Pin: // expander 2 port A
		enc_interrupt_sent(encoderProc, EXP_2_ADDR, 0);
		break;
	case EXP_INTR_C_Pin: // expander 3 port A
		enc_interrupt_sent(encoderProc, EXP_3_ADDR, 0);
		break;
	default:
		break;
	}

}

// control callback implementations
void encoderTurn(uint8_t enc, uint8_t clockwise) {
	handle_encoder_turn(synthProc, enc, clockwise);
}

void onClick(uint8_t btn) {
	handle_on_click(synthProc, btn);
}

void onPressStart(uint8_t btn) {
	handle_on_press_start(synthProc, btn);
}

void onPressEnd(uint8_t btn) {
	handle_on_press_end(synthProc, btn);
}

void duringPress(uint8_t btn) {
	handle_during_press(synthProc, btn);
}

/* USER CODE END 4 */

void Error_Handler(void)
{
	__disable_irq();
	while (1) {
	}
}
